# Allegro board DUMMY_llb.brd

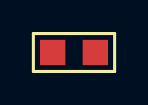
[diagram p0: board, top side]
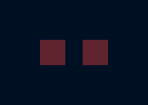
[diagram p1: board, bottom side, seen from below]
No outline. copper layers: TOP, BOTTOM. Coordinates in mm from the lowest, leftmost part position.

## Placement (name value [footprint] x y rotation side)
SMR0805  -  [SMR0805]  0 0 0 top

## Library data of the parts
SMR0805 = SMR0805

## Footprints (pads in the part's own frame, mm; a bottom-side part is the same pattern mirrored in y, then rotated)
SMR0805
  rect 1.27x1.27 smd: 1(0,0) 2(2.134,0)

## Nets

Pads without a net: SMR0805 1 2
